VERSION 5.8 ;
BUSBITCHARS "[]" ;
DIVIDERCHAR "/" ;
UNITS
    DATABASE MICRONS 1000 ;
END UNITS

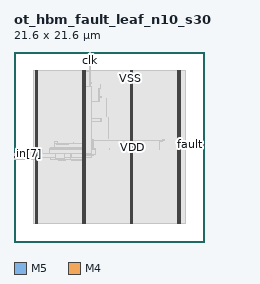
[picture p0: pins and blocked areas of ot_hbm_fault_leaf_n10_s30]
MACRO ot_hbm_fault_leaf_n10_s30
  FOREIGN ot_hbm_fault_leaf_n10_s30 0 0 ;
  CLASS BLOCK ;
  SIZE 21.6 BY 21.6 ;
  PIN clk
    DIRECTION INPUT ;
    USE SIGNAL ;
    PORT
      LAYER M5 ;
        RECT  8.592 21.516 8.616 21.6 ;
    END
  END clk
  PIN fault
    DIRECTION OUTPUT ;
    USE SIGNAL ;
    PORT
      LAYER M4 ;
        RECT  21.516 11.088 21.6 11.112 ;
    END
  END fault
  PIN in[0]
    DIRECTION INPUT ;
    USE SIGNAL ;
    PORT
      LAYER M4 ;
        RECT  0 9.36 0.084 9.384 ;
    END
  END in[0]
  PIN in[1]
    DIRECTION INPUT ;
    USE SIGNAL ;
    PORT
      LAYER M4 ;
        RECT  0 9.456 0.084 9.48 ;
    END
  END in[1]
  PIN in[2]
    DIRECTION INPUT ;
    USE SIGNAL ;
    PORT
      LAYER M4 ;
        RECT  0 9.552 0.084 9.576 ;
    END
  END in[2]
  PIN in[3]
    DIRECTION INPUT ;
    USE SIGNAL ;
    PORT
      LAYER M4 ;
        RECT  0 9.648 0.084 9.672 ;
    END
  END in[3]
  PIN in[4]
    DIRECTION INPUT ;
    USE SIGNAL ;
    PORT
      LAYER M4 ;
        RECT  0 9.744 0.084 9.768 ;
    END
  END in[4]
  PIN in[5]
    DIRECTION INPUT ;
    USE SIGNAL ;
    PORT
      LAYER M4 ;
        RECT  0 9.84 0.084 9.864 ;
    END
  END in[5]
  PIN in[6]
    DIRECTION INPUT ;
    USE SIGNAL ;
    PORT
      LAYER M4 ;
        RECT  0 9.936 0.084 9.96 ;
    END
  END in[6]
  PIN in[7]
    DIRECTION INPUT ;
    USE SIGNAL ;
    PORT
      LAYER M4 ;
        RECT  0 10.032 0.084 10.056 ;
    END
  END in[7]
  PIN in[8]
    DIRECTION INPUT ;
    USE SIGNAL ;
    PORT
      LAYER M4 ;
        RECT  0 10.128 0.084 10.152 ;
    END
  END in[8]
  PIN in[9]
    DIRECTION INPUT ;
    USE SIGNAL ;
    PORT
      LAYER M4 ;
        RECT  0 10.224 0.084 10.248 ;
    END
  END in[9]
  PIN rst_n
    DIRECTION INPUT ;
    USE SIGNAL ;
    PORT
      LAYER M5 ;
        RECT  8.688 21.516 8.712 21.6 ;
    END
  END rst_n
  PIN VDD
    DIRECTION INOUT ;
    USE POWER ;
    PORT
      LAYER M5 ;
        RECT  18.792 2.151 18.912 19.449 ;
        RECT  13.392 2.151 13.512 19.449 ;
        RECT  7.992 2.151 8.112 19.449 ;
        RECT  2.592 2.151 2.712 19.449 ;
    END
  END VDD
  PIN VSS
    DIRECTION INOUT ;
    USE GROUND ;
    PORT
      LAYER M5 ;
        RECT  18.6 2.137 18.72 19.463 ;
        RECT  13.2 2.137 13.32 19.463 ;
        RECT  7.8 2.137 7.92 19.463 ;
        RECT  2.4 2.137 2.52 19.463 ;
    END
  END VSS
  OBS
    LAYER RVTN ;
     RECT  2.16 2.16 19.44 2.295 ;
     RECT  2.16 2.565 19.44 2.835 ;
     RECT  2.16 3.105 19.44 3.375 ;
     RECT  2.16 3.645 19.44 3.915 ;
     RECT  2.16 4.185 19.44 4.455 ;
     RECT  2.16 4.725 19.44 4.995 ;
     RECT  2.16 5.265 19.44 5.535 ;
     RECT  2.16 5.805 19.44 6.075 ;
     RECT  2.16 6.345 19.44 6.615 ;
     RECT  2.16 6.885 19.44 7.155 ;
     RECT  2.16 7.425 19.44 7.695 ;
     RECT  2.16 7.965 19.44 8.235 ;
     RECT  2.16 8.505 19.44 8.775 ;
     RECT  2.16 9.045 19.44 9.315 ;
     RECT  2.16 9.585 19.44 9.855 ;
     RECT  2.16 10.125 19.44 10.395 ;
     RECT  2.16 10.665 19.44 10.935 ;
     RECT  2.16 11.205 19.44 11.475 ;
     RECT  2.16 11.745 19.44 12.015 ;
     RECT  2.16 12.285 19.44 12.555 ;
     RECT  2.16 12.825 19.44 13.095 ;
     RECT  2.16 13.365 19.44 13.635 ;
     RECT  2.16 13.905 19.44 14.175 ;
     RECT  2.16 14.445 19.44 14.715 ;
     RECT  2.16 14.985 19.44 15.255 ;
     RECT  2.16 15.525 19.44 15.795 ;
     RECT  2.16 16.065 19.44 16.335 ;
     RECT  2.16 16.605 19.44 16.875 ;
     RECT  2.16 17.145 19.44 17.415 ;
     RECT  2.16 17.685 19.44 17.955 ;
     RECT  2.16 18.225 19.44 18.495 ;
     RECT  2.16 18.765 19.44 19.035 ;
     RECT  2.16 19.305 19.44 19.44 ;
    LAYER RVTP ;
     RECT  2.16 2.295 19.44 2.565 ;
     RECT  2.16 2.835 19.44 3.105 ;
     RECT  2.16 3.375 19.44 3.645 ;
     RECT  2.16 3.915 19.44 4.185 ;
     RECT  2.16 4.455 19.44 4.725 ;
     RECT  2.16 4.995 19.44 5.265 ;
     RECT  2.16 5.535 19.44 5.805 ;
     RECT  2.16 6.075 19.44 6.345 ;
     RECT  2.16 6.615 19.44 6.885 ;
     RECT  2.16 7.155 19.44 7.425 ;
     RECT  2.16 7.695 19.44 7.965 ;
     RECT  2.16 8.235 19.44 8.505 ;
     RECT  2.16 8.775 19.44 9.045 ;
     RECT  2.16 9.315 19.44 9.585 ;
     RECT  2.16 9.855 19.44 10.125 ;
     RECT  2.16 10.395 19.44 10.665 ;
     RECT  2.16 10.935 19.44 11.205 ;
     RECT  2.16 11.475 19.44 11.745 ;
     RECT  2.16 12.015 19.44 12.285 ;
     RECT  2.16 12.555 19.44 12.825 ;
     RECT  2.16 13.095 19.44 13.365 ;
     RECT  2.16 13.635 19.44 13.905 ;
     RECT  2.16 14.175 19.44 14.445 ;
     RECT  2.16 14.715 19.44 14.985 ;
     RECT  2.16 15.255 19.44 15.525 ;
     RECT  2.16 15.795 19.44 16.065 ;
     RECT  2.16 16.335 19.44 16.605 ;
     RECT  2.16 16.875 19.44 17.145 ;
     RECT  2.16 17.415 19.44 17.685 ;
     RECT  2.16 17.955 19.44 18.225 ;
     RECT  2.16 18.495 19.44 18.765 ;
     RECT  2.16 19.035 19.44 19.305 ;
    LAYER M1 ;
     RECT  2.16 2.151 19.44 19.449 ;
    LAYER M2 ;
     RECT  2.16 2.151 19.44 19.449 ;
     RECT  19.44 11.106 19.931 11.124 ;
    LAYER M3 ;
     RECT  2.415 2.143 2.505 2.413 ;
     RECT  7.815 2.143 7.905 2.413 ;
     RECT  13.215 2.143 13.305 2.413 ;
     RECT  18.615 2.143 18.705 2.413 ;
     RECT  5.004 9.211 5.022 9.247 ;
     RECT  7.815 2.413 8.097 9.247 ;
     RECT  7.2 9.247 8.097 9.319 ;
     RECT  2.415 2.413 2.697 9.355 ;
     RECT  5.004 9.247 5.814 9.391 ;
     RECT  6.552 9.319 8.097 9.391 ;
     RECT  2.304 9.355 2.697 9.589 ;
     RECT  4.104 9.391 8.097 9.625 ;
     RECT  2.304 9.589 3.258 9.835 ;
     RECT  4.104 9.625 8.802 9.859 ;
     RECT  2.232 9.835 3.258 9.887 ;
     RECT  4.104 9.859 8.982 9.895 ;
     RECT  4.068 9.895 8.982 9.931 ;
     RECT  2.268 9.887 3.258 10.463 ;
     RECT  4.068 9.931 9.306 10.463 ;
     RECT  4.068 10.463 8.097 10.589 ;
     RECT  8.964 10.463 9.306 10.589 ;
     RECT  2.415 10.463 3.042 10.661 ;
     RECT  10.8 10.561 10.818 10.661 ;
     RECT  4.104 10.589 8.097 10.733 ;
     RECT  19.908 11.083 19.926 11.129 ;
     RECT  4.644 10.733 8.097 11.165 ;
     RECT  5.724 11.165 8.097 11.171 ;
     RECT  5.724 11.171 5.742 11.201 ;
     RECT  6.768 11.171 8.097 11.201 ;
     RECT  18.615 2.413 18.897 11.281 ;
     RECT  6.768 11.201 6.786 11.309 ;
     RECT  4.644 11.165 4.95 11.399 ;
     RECT  18.432 11.281 18.897 11.399 ;
     RECT  4.644 11.399 4.662 11.435 ;
     RECT  16.488 10.561 16.506 11.479 ;
     RECT  16.488 11.479 16.902 11.515 ;
     RECT  16.344 11.515 17.082 11.552 ;
     RECT  8.964 10.589 8.982 11.669 ;
     RECT  16.884 11.552 17.082 11.669 ;
     RECT  7.815 11.201 8.097 12.325 ;
     RECT  7.815 12.325 8.802 12.509 ;
     RECT  7.815 12.509 8.262 12.941 ;
     RECT  9.936 13.675 9.954 13.945 ;
     RECT  9.792 13.945 9.954 13.997 ;
     RECT  10.692 11.821 10.71 14.099 ;
     RECT  10.512 14.215 10.53 16.259 ;
     RECT  9.648 15.979 9.666 16.411 ;
     RECT  9.648 16.411 9.954 16.529 ;
     RECT  9.648 16.529 9.666 17.447 ;
     RECT  7.815 12.941 8.097 17.659 ;
     RECT  9.828 17.455 9.846 17.879 ;
     RECT  7.815 17.659 8.694 18.031 ;
     RECT  7.815 18.031 8.838 18.149 ;
     RECT  2.415 10.661 2.697 19.187 ;
     RECT  7.815 18.149 8.73 19.187 ;
     RECT  13.215 2.413 13.497 19.187 ;
     RECT  18.615 11.399 18.897 19.187 ;
     RECT  8.712 19.187 8.73 19.373 ;
     RECT  2.415 19.187 2.505 19.457 ;
     RECT  7.815 19.187 7.905 19.457 ;
     RECT  13.215 19.187 13.305 19.457 ;
     RECT  18.615 19.187 18.705 19.457 ;
    LAYER M4 ;
     RECT  0.06 9.36 2.408 10.248 ;
     RECT  2.408 2.148 2.512 19.452 ;
     RECT  2.512 2.418 2.704 19.182 ;
     RECT  2.704 9.552 4.705 10.104 ;
     RECT  4.705 9.456 5.717 10.104 ;
     RECT  4.777 11.136 6.221 11.16 ;
     RECT  5.717 9.552 6.501 10.104 ;
     RECT  6.501 9.648 7.808 10.104 ;
     RECT  7.808 2.148 7.912 19.452 ;
     RECT  7.912 2.418 8.104 19.368 ;
     RECT  8.104 9.888 8.165 10.44 ;
     RECT  8.165 10.08 8.243 10.44 ;
     RECT  8.104 11.52 8.579 13.992 ;
     RECT  8.104 19.344 8.741 19.368 ;
     RECT  8.243 10.08 8.819 10.104 ;
     RECT  8.579 11.52 8.819 12.504 ;
     RECT  8.104 17.664 8.819 17.688 ;
     RECT  8.104 15.984 9.677 16.008 ;
     RECT  8.579 13.68 9.821 13.992 ;
     RECT  9.821 13.68 9.965 13.704 ;
     RECT  8.819 11.52 13.208 11.544 ;
     RECT  13.208 2.148 13.312 19.452 ;
     RECT  13.312 2.418 13.504 19.182 ;
     RECT  13.504 11.52 16.373 11.544 ;
     RECT  18.608 2.148 18.712 19.452 ;
     RECT  18.712 2.418 18.904 19.182 ;
     RECT  19.897 11.088 21.564 11.112 ;
    LAYER M5 ;
     RECT  2.4 2.137 2.52 2.151 ;
     RECT  7.8 2.137 7.92 2.151 ;
     RECT  13.2 2.137 13.32 2.151 ;
     RECT  18.6 2.137 18.72 2.151 ;
     RECT  6.432 9.541 6.456 9.923 ;
     RECT  7.8 2.151 8.112 10.069 ;
     RECT  7.8 10.069 8.808 17.699 ;
     RECT  7.8 17.699 8.616 19.333 ;
     RECT  2.4 2.151 2.712 19.449 ;
     RECT  13.2 2.151 13.512 19.449 ;
     RECT  18.6 2.151 18.912 19.449 ;
     RECT  2.4 19.449 2.52 19.463 ;
     RECT  7.8 19.333 8.712 19.463 ;
     RECT  13.2 19.449 13.32 19.463 ;
     RECT  18.6 19.449 18.72 19.463 ;
     RECT  8.592 19.463 8.712 21.584 ;
  END
END ot_hbm_fault_leaf_n10_s30
END LIBRARY
